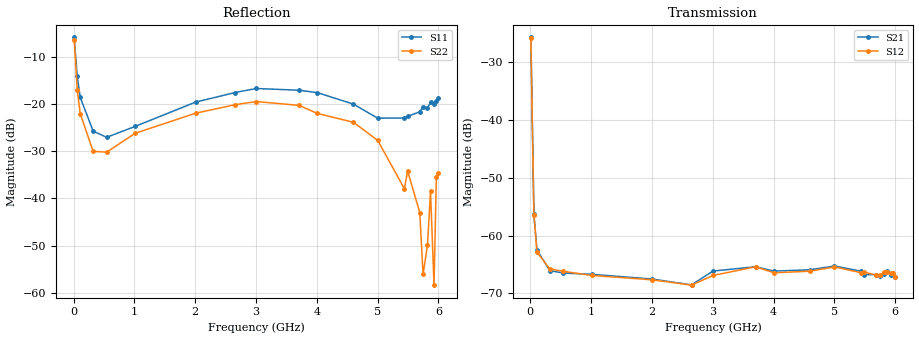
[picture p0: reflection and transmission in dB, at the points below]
!Agilent Technologies,E5071C,MY46316741,A.11.02
!Date: Tue Oct 20 14:46:17 2020
!Data & Calibration Information:
!Freq	S11:SOLT4(ON)	S21:SOLT4(ON)	S12:SOLT4(ON)	S22:SOLT4(ON)
!PortZ  Port1:50+j0  Port2:50+j0
!Above PortZ is port z conversion or system Z0 setting when saving the data.
!When reading, reference impedance value at option line is always used.
# Hz S dB R 50
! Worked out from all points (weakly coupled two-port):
!   1561 points, 10 MHz to 6 GHz, reference 50 ohm
!   highest |S21| = -25.76 dB at 10 MHz (marker M1); lowest = -68.5 dB at 2.652 GHz (marker M2)
!   lowest |S11| = -27.0 dB at 543.7 MHz (marker M3), VSWR 1.09, Z = 46.6 + j2.64 ohm
!   |S11| at or under -10 dB: 29.83 MHz to end of sweep
!   |S22| runs from -66.8 to -6.3 dB; largest |S21 - S12| = 0.00061
!   S11 on the Smith chart (normalised r, x): 10 MHz: 1.72, -1.38; 3.708 GHz: 0.78, -0.11; 4.602 GHz: 0.86, +0.13; 6 GHz: 1.05, -0.24
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1e7  -5.85 -35.5  -25.76 -113.0  -25.85 -112.7  -6.31 -43.2
5.991667e7  -14.14 -84.3  -56.33 -126.6  -56.42 -126.4  -16.97 -92.5
1.098333e8  -18.59 -107.3  -62.52 -93.9  -62.87 -91.5  -22.05 -113.0
3.210192e8  -25.72 -170.1  -66.06 -71.9  -65.77 -69.5  -30.01 177.8
5.437244e8  -27.04 140.5  -66.49 -89.2  -66.19 -85.9  -30.19 120.2
1.012173e9  -24.73 67.9  -66.70 -140.7  -66.90 -139.6  -26.19 46.7
2.006667e9  -19.57 -25.5  -67.52 92.9  -67.65 94.4  -21.93 -43.7
2.651744e9  -17.56 -77.1  -68.53 11.9  -68.57 13.7  -20.14 -94.4
3.005e9  -16.69 -101.6  -66.14 -22.8  -66.90 -28.9  -19.46 -120.0
3.707673e9  -17.06 -150.8  -65.39 -126.6  -65.40 -127.6  -20.27 -161.0
4.007173e9  -17.56 179.3  -66.15 -168.6  -66.44 -166.3  -21.97 163.1
4.602333e9  -20.01 132.8  -65.91 129.6  -66.16 129.4  -23.86 134.9
5.001667e9  -22.99 68.9  -65.27 72.2  -65.43 73.2  -27.70 93.9
5.439397e9  -22.95 1.9  -66.16 19.7  -66.42 18.9  -37.94 68.2
5.493154e9  -22.60 -7.1  -66.77 15.0  -66.31 15.3  -34.22 67.3
5.692821e9  -21.63 -32.0  -66.74 -7.3  -66.87 -7.7  -42.99 44.8
5.746577e9  -20.51 -46.1  -67.01 -13.0  -66.89 -12.1  -56.07 -118.1
5.819532e9  -20.87 -48.7  -66.67 -19.0  -66.33 -19.7  -49.98 121.1
5.869449e9  -19.60 -59.5  -66.15 -24.6  -66.29 -24.9  -38.50 -115.7
5.927045e9  -19.88 -58.6  -66.77 -30.7  -66.48 -32.3  -58.39 138.2
5.965442e9  -19.42 -69.3  -66.64 -35.9  -66.49 -37.1  -35.43 -160.0
6e9  -18.67 -71.3  -67.09 -39.1  -67.22 -38.2  -34.66 -116.6
